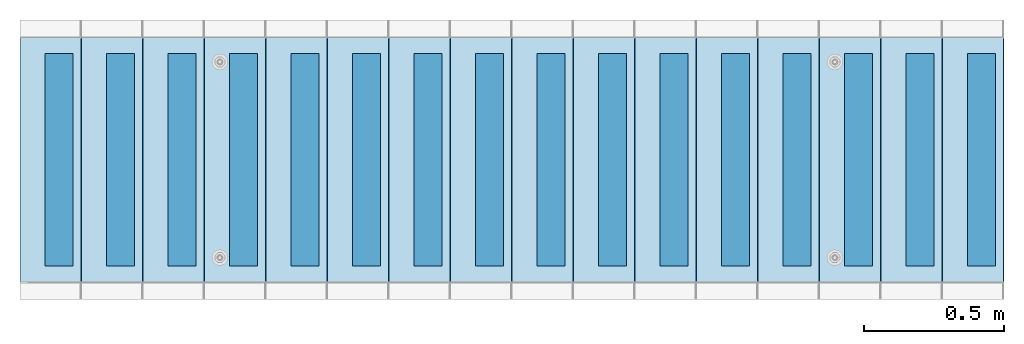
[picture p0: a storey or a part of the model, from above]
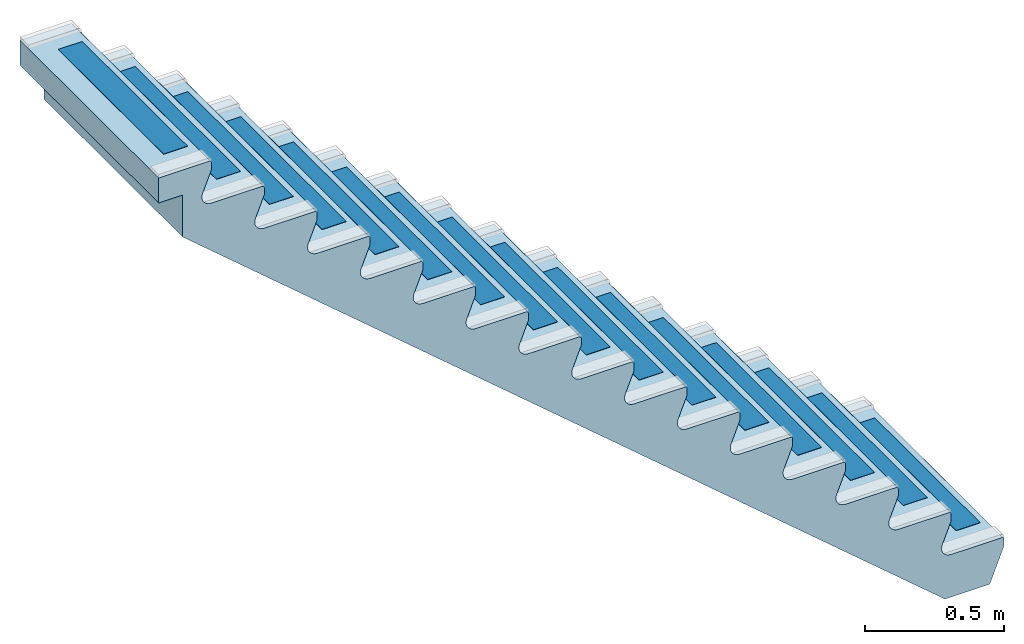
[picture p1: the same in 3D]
Properties of the parts of a building model (IFC2X3)

# File
Description: ViewDefinition[CoordinationView_V2.0, QuantityTakeOffAddOnView], Option [BaseQuantities:On], Option [GridExport:On], Option [Assemblies:On], Option [Bolts:Off], Option [Rebars:Off], Option [PourObjects:Off], Option [Welds:Off], Option [SurfaceTreatments:On], Option [LocationBy:0], Option [ViewColors:On], Option [SectionedSpine:Off], Option [PropertySets:On], Option [Export all:Off]
File name: MB-Export.ifc
Time: 2024-04-11T09:45:34
Author: DESKTOP-MAH8VVD\Kay Huls
Organization: Structural Designer
Written by: IFC Database Version: Work
Made in: Tekla Structures 2021 Service Pack 11, IFC Export Version: 4.0.0.0 Nov 13 2022

# IfcBuildingStorey, Undefined
In: Undefined
Elevation: 0 mm

# IfcBeam: 100*2 (16)
In: Undefined
Description: 100*2; Material: MISCELLANEOUS/RUBBER_HARD
Mombarg - Betonmengsel: STD
Tekla Common - Phase: 1; Class: 4
Tekla Quantity - Weight: 0.17 kg; Volume: 0 m3; Gross footprint area: 0.076 m2; Area per tons: 852.193 m2; Net surface area: 0.155 m2; Height: 2 mm; Width: 100 mm; Length: 760 mm
Pset_BeamCommon - IsExternal: no; LoadBearing: no; Reference: AS02
BaseQuantities - Length: 760 mm; OuterSurfaceArea: 0.15544 m2; NetVolume: 0.000152 m3; NetWeight: 0.1824 kg
Name | Bottom elevation | Top elevation
AntiSkid | +2.999 | +3.001
AntiSkid | +2.812 | +2.814
AntiSkid | +2.624 | +2.626
AntiSkid | +2.437 | +2.439
AntiSkid | +2.249 | +2.251
AntiSkid | +2.062 | +2.064
AntiSkid | +1.874 | +1.876
AntiSkid | +1.687 | +1.689
AntiSkid | +1.499 | +1.501
AntiSkid | +1.312 | +1.314
AntiSkid | +1.124 | +1.126
AntiSkid | +0.937 | +0.939
AntiSkid | +0.749 | +0.751
AntiSkid | +0.562 | +0.564
AntiSkid | +0.374 | +0.376
AntiSkid | +0.187 | +0.189

# IfcBeam: D14 (4)
In: Undefined
Description: D14; Material: STEEL/8.8
Mombarg - Betonmengsel: STD
Tekla Common - Finish: elec.verz.; Phase: 1; Class: 101
Tekla Quantity - Weight: 0.17 kg; Volume: 0 m3; Gross footprint area: 0 m2; Area per tons: 71.149 m2; Net surface area: 0.012 m2; Height: 35 mm; Width: 35 mm; Length: 90 mm
Pset_BeamCommon - IsExternal: no; LoadBearing: no; Reference: ITSV19
BaseQuantities - Length: 90 mm; OuterSurfaceArea: 0.0118802 m2; NetVolume: 0.0000208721 m3; NetWeight: 0.166977 kg
Name | Bottom elevation | Top elevation
2 x HBS_anker | +2.338 | +2.428
2 x HBS_anker | +0.463 | +0.553

# IfcBeam: ELD58*58*50*50 (4)
In: Undefined
Description: ELD58*58*50*50; Material: MISCELLANEOUS/RUBBER_HARD
Mombarg - Betonmengsel: STD
Tekla Common - Phase: 1; Class: 111
Tekla Quantity - Weight: 0.03 kg; Volume: 0 m3; Gross footprint area: 0.003 m2; Area per tons: 234.76 m2; Net surface area: 0.006 m2; Height: 58 mm; Width: 58 mm; Length: 10 mm
Pset_BeamCommon - IsExternal: no; LoadBearing: no; Reference: ITSV9
BaseQuantities - Length: 10 mm; OuterSurfaceArea: 0.00629877 m2; NetVolume: 0.0000223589 m3; NetWeight: 0.0268307 kg
Name | Bottom elevation | Top elevation
2 x Spijkerflens | +2.428 | +2.438
2 x Spijkerflens | +0.553 | +0.563

# IfcCovering: elec.verz. (4)
In: Undefined
Material: Undefined/Undefined

# IfcElementAssembly (21)
In: Undefined
Mombarg - Betonmengsel: STD
Tekla Assembly - Phase: 1
Name | Assembly/Cast unit weight (kg) | Assembly/Cast unit bottom elevation | Assembly/Cast unit top elevation | Assembly/Cast unit position code | Assembly/Cast unit Mark | Width (mm)
Trap met bomen | 2348.9 | -0.000 | +3.015 | E-I/6 | STR02 | 1000 | PredefinedType: REINFORCEMENT_UNIT; Mombarg - Dekking 2: 20 mm; Dekking 1: 20 mm; Milieuklasse 3: XC2; Milieuklasse 2: XC1; Milieuklasse 1: XC3; Afwerking malzijde: zichtwerk; Afwerking stortzijde: R; Antislip profiel: GIAN1; NL-SfB Codering: 24.11; NL-SfB Omschrijving: trappen en hellingen; trappen, rechte steektrappen; Tekla Assembly - Cast unit type: Prefab; Cast unit rebar weight: 0 kg
2 x HBS_anker | 0.2 | +2.338 | +2.438 | F/6 | 50101 | 58 | PredefinedType: RIGID_FRAME
2 x HBS_anker | 0.2 | +0.463 | +0.563 | H/6 | 50101 | 58 | PredefinedType: RIGID_FRAME
AntiSkid | 0.2 | +2.999 | +3.001 | F/6 | AS02 | 100
AntiSkid | 0.2 | +2.812 | +2.814 | F/6 | AS02 | 100
AntiSkid | 0.2 | +2.624 | +2.626 | F/6 | AS02 | 100
AntiSkid | 0.2 | +2.437 | +2.439 | F/6 | AS02 | 100
AntiSkid | 0.2 | +2.249 | +2.251 | F-G/6 | AS02 | 100
AntiSkid | 0.2 | +2.062 | +2.064 | G/6 | AS02 | 100
AntiSkid | 0.2 | +1.874 | +1.876 | G/6 | AS02 | 100
AntiSkid | 0.2 | +1.687 | +1.689 | G/6 | AS02 | 100
AntiSkid | 0.2 | +1.499 | +1.501 | G/6 | AS02 | 100
AntiSkid | 0.2 | +1.312 | +1.314 | H/6 | AS02 | 100
AntiSkid | 0.2 | +1.124 | +1.126 | H/6 | AS02 | 100
AntiSkid | 0.2 | +0.937 | +0.939 | H/6 | AS02 | 100
AntiSkid | 0.2 | +0.749 | +0.751 | H/6 | AS02 | 100
AntiSkid | 0.2 | +0.562 | +0.564 | H-I/6 | AS02 | 100
AntiSkid | 0.2 | +0.374 | +0.376 | I/6 | AS02 | 100
AntiSkid | 0.2 | +0.187 | +0.189 | I/6 | AS02 | 100

# IfcSlab: 1000*298.1, Trap met bomen
In: Undefined
Description: 1000*298.1; PredefinedType: FLOOR; Material: CONCRETE/C55/67
Mombarg - Dekking 2: 20 mm; Dekking 1: 20 mm; Milieuklasse 3: XC2; Milieuklasse 2: XC1; Milieuklasse 1: XC3; Afwerking malzijde: zichtwerk; Afwerking stortzijde: R; Antislip profiel: GIAN1; Betonmengsel: STD; NL-SfB Codering: 24.11; NL-SfB Omschrijving: trappen en hellingen; trappen, rechte steektrappen
Tekla Common - Bottom elevation: -0.000; Top elevation: +3.000; Phase: 1; Class: 1
Tekla Quantity - Weight: 2328.06 kg; Volume: 0.97 m3; Gross footprint area: 0.21 m2; Area per tons: 5.845 m2; Net surface area: 13.606 m2; Height: 298.1 mm; Width: 1000 mm; Length: 4580 mm
Pset_SlabCommon - IsExternal: no; LoadBearing: no; Reference: P9
BaseQuantities - Width: 1000 mm; NetVolume: 0.970023 m3; NetArea: 0.21 m2; NetWeight: 2328.06 kg

# IfcSlab: 60*25 (32)
In: Undefined
Description: 60*25; PredefinedType: FLOOR; Material: CONCRETE/C55/67
Mombarg - Betonmengsel: STD
Tekla Common - Phase: 1; Class: 1
Tekla Quantity - Volume: 0 m3; Gross footprint area: 0.013 m2; Height: 25 mm; Width: 66.7 mm
Pset_SlabCommon - IsExternal: no; LoadBearing: no
BaseQuantities - Width: 66.6987 mm
Name | Bottom elevation | Top elevation | Weight (kg) | Area per tons (m2) | Net surface area (m2) | Length (mm) | Reference | NetVolume (m3) | NetArea (m2) | NetWeight (kg)
Ridge | +2.990 | +3.015 | 0.49 | 74.503 | 0.037 | 220 | P8 | 0.000204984 | 0.0126 | 0.491963
Ridge | +2.990 | +3.015 | 0.49 | 74.408 | 0.037 | 220 | P8 | 0.000205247 | 0.0126 | 0.492594
Ridge | +2.803 | +2.828 | 0.54 | 75.114 | 0.04 | 251.2 | P7 | 0.00022459 | 0.0144735 | 0.539017
Ridge | +2.803 | +2.828 | 0.54 | 75.136 | 0.04 | 251.2 | P6 | 0.000224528 | 0.0144735 | 0.538868
Ridge | +2.615 | +2.640 | 0.54 | 75.114 | 0.04 | 251.2 | P7 | 0.00022459 | 0.0144735 | 0.539017
Ridge | +2.615 | +2.640 | 0.54 | 75.136 | 0.04 | 251.2 | P6 | 0.000224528 | 0.0144735 | 0.538868
Ridge | +2.428 | +2.453 | 0.54 | 75.114 | 0.04 | 251.2 | P7 | 0.00022459 | 0.0144735 | 0.539017
Ridge | +2.428 | +2.453 | 0.54 | 75.136 | 0.04 | 251.2 | P6 | 0.000224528 | 0.0144735 | 0.538868
Ridge | +2.240 | +2.265 | 0.54 | 75.114 | 0.04 | 251.2 | P7 | 0.00022459 | 0.0144735 | 0.539017
Ridge | +2.240 | +2.265 | 0.54 | 75.136 | 0.04 | 251.2 | P6 | 0.000224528 | 0.0144735 | 0.538868
Ridge | +2.053 | +2.078 | 0.54 | 75.114 | 0.04 | 251.2 | P7 | 0.00022459 | 0.0144735 | 0.539017
Ridge | +2.053 | +2.078 | 0.54 | 75.136 | 0.04 | 251.2 | P6 | 0.000224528 | 0.0144735 | 0.538868
Ridge | +1.865 | +1.890 | 0.54 | 75.114 | 0.04 | 251.2 | P7 | 0.00022459 | 0.0144735 | 0.539017
Ridge | +1.865 | +1.890 | 0.54 | 75.136 | 0.04 | 251.2 | P6 | 0.000224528 | 0.0144735 | 0.538868
Ridge | +1.678 | +1.703 | 0.54 | 75.114 | 0.04 | 251.2 | P7 | 0.00022459 | 0.0144735 | 0.539017
Ridge | +1.678 | +1.703 | 0.54 | 75.136 | 0.04 | 251.2 | P6 | 0.000224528 | 0.0144735 | 0.538868
Ridge | +1.490 | +1.515 | 0.54 | 75.114 | 0.04 | 251.2 | P7 | 0.00022459 | 0.0144735 | 0.539017
Ridge | +1.490 | +1.515 | 0.54 | 75.136 | 0.04 | 251.2 | P6 | 0.000224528 | 0.0144735 | 0.538868
Ridge | +1.303 | +1.328 | 0.54 | 75.114 | 0.04 | 251.2 | P7 | 0.00022459 | 0.0144735 | 0.539017
Ridge | +1.303 | +1.328 | 0.54 | 75.136 | 0.04 | 251.2 | P6 | 0.000224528 | 0.0144735 | 0.538868
Ridge | +1.115 | +1.140 | 0.54 | 75.114 | 0.04 | 251.2 | P7 | 0.00022459 | 0.0144735 | 0.539017
Ridge | +1.115 | +1.140 | 0.54 | 75.136 | 0.04 | 251.2 | P6 | 0.000224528 | 0.0144735 | 0.538868
Ridge | +0.928 | +0.953 | 0.54 | 75.114 | 0.04 | 251.2 | P7 | 0.00022459 | 0.0144735 | 0.539017
Ridge | +0.928 | +0.953 | 0.54 | 75.136 | 0.04 | 251.2 | P6 | 0.000224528 | 0.0144735 | 0.538868
Ridge | +0.740 | +0.765 | 0.54 | 75.114 | 0.04 | 251.2 | P7 | 0.00022459 | 0.0144735 | 0.539017
Ridge | +0.740 | +0.765 | 0.54 | 75.136 | 0.04 | 251.2 | P6 | 0.000224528 | 0.0144735 | 0.538868
Ridge | +0.553 | +0.578 | 0.54 | 75.114 | 0.04 | 251.2 | P7 | 0.00022459 | 0.0144735 | 0.539017
Ridge | +0.553 | +0.578 | 0.54 | 75.136 | 0.04 | 251.2 | P6 | 0.000224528 | 0.0144735 | 0.538868
Ridge | +0.365 | +0.390 | 0.54 | 75.114 | 0.04 | 251.2 | P7 | 0.00022459 | 0.0144735 | 0.539017
Ridge | +0.365 | +0.390 | 0.54 | 75.136 | 0.04 | 251.2 | P6 | 0.000224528 | 0.0144735 | 0.538868
Ridge | +0.178 | +0.203 | 0.54 | 75.114 | 0.04 | 251.2 | P7 | 0.00022459 | 0.0144735 | 0.539017
Ridge | +0.178 | +0.203 | 0.54 | 75.136 | 0.04 | 251.2 | P6 | 0.000224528 | 0.0144735 | 0.538868
